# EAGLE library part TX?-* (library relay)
TX Relais NAiS TX-D RELAYS HIGH INSULATION Conforming to the supplementary insulation class of EN Standards (EN41003) Source: http://www.mew-europe.com/.. en_ds_61022_0007.pdf TX-S RELAYS SMALL POLARIZED RELAY WITH HIGH SENSITIVITY 50mW Source: http://www.mew-europe.com/.. en_ds_61022_0022.pdf

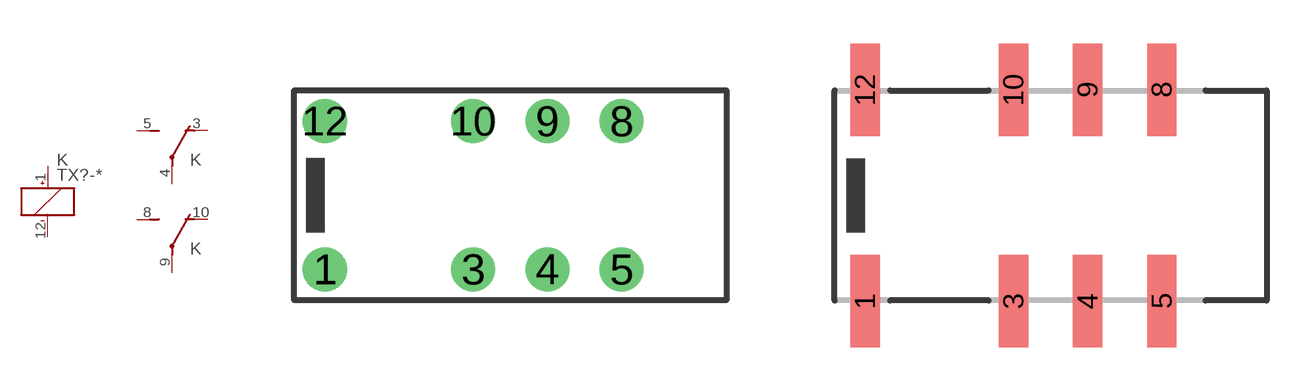
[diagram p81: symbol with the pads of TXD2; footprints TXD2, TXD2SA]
Designator prefix K; gates _=K+- G$1=U G$2=U

## TXD2-1.5V, TXD2-12V, TXD2-24V, TXD2-3V, TXD2-4.5V, TXD2-5V, TXD2-6V, TXD2-9V  [TXD2]
1  _:+  pas
3  G$1:O  pas
4  G$1:P  pas
5  G$1:S  pas
8  G$2:S  pas
9  G$2:P  pas
10  G$2:O  pas
12  _:-  pas

## TXD2SA-1.5V, TXD2SA-12V, TXD2SA-24V, TXD2SA-3V, TXD2SA-4.5V, TXD2SA-5V, TXD2SA-6V, TXD2SA-9V  [TXD2SA]
Pads as for TXD2

## TXD2SL-1.5V, TXD2SL-12V, TXD2SL-24V, TXD2SL-3V, TXD2SL-4.5V, TXD2SL-5V, TXD2SL-6V, TXD2SL-9V  [TXD2SL]
Pads as for TXD2

## TXD2SS-1.5V, TXD2SS-12V, TXD2SS-24V, TXD2SS-3V, TXD2SS-4.5V, TXD2SS-5V, TXD2SS-6V, TXD2SS-9V  [TXD2SS]
Pads as for TXD2

## TXD2-L-1.5V, TXD2-L-12V, TXD2-L-24V, TXD2-L-3V, TXD2-L-4.5V, TXD2-L-5V, TXD2-L-6V, TXD2-L-9V  [TXD2]
1  _:-  pas
3  G$1:O  pas
4  G$1:P  pas
5  G$1:S  pas
8  G$2:S  pas
9  G$2:P  pas
10  G$2:O  pas
12  _:+  pas

## TXD2SA-L-1.5V, TXD2SA-L-12V, TXD2SA-L-24V, TXD2SA-L-3V, TXD2SA-L-4.5V, TXD2SA-L-5V, TXD2SA-L-6V, TXD2SA-L-9V  [TXD2SA]
Pads as for TXD2

## TXD2SL-L-1.5V, TXD2SL-L-12V, TXD2SL-L-24V, TXD2SL-L-3V, TXD2SL-L-4.5V, TXD2SL-L-5V, TXD2SL-L-6V, TXD2SL-L-9V  [TXD2SL]
Pads as for TXD2

## TXD2SS-L-1.5V, TXD2SS-L-12V, TXD2SS-L-24V, TXD2SS-L-3V, TXD2SS-L-4.5V, TXD2SS-L-5V, TXD2SS-L-6V, TXD2SS-L-9V  [TXD2SS]
Pads as for TXD2

## TXD2-2M-1.5V, TXD2-2M-12V, TXD2-2M-24V, TXD2-2M-3V, TXD2-2M-4.5V, TXD2-2M-5V, TXD2-2M-6V, TXD2-2M-9V  [TXD2]
Pads as for TXD2

## TXD2SA-2M-1.5V, TXD2SA-2M-12V, TXD2SA-2M-24V, TXD2SA-2M-3V, TXD2SA-2M-4.5V, TXD2SA-2M-5V, TXD2SA-2M-6V, TXD2SA-2M-9V  [TXD2SA]
Pads as for TXD2

## TXD2SL-2M-1.5V, TXD2SL-2M-12V, TXD2SL-2M-24V, TXD2SL-2M-3V, TXD2SL-2M-4.5V, TXD2SL-2M-5V, TXD2SL-2M-6V, TXD2SL-2M-9V  [TXD2SL]
Pads as for TXD2

## TXD2SS-2M-1.5V, TXD2SS-2M-12V, TXD2SS-2M-24V, TXD2SS-2M-3V, TXD2SS-2M-4.5V, TXD2SS-2M-5V, TXD2SS-2M-6V, TXD2SS-2M-9V  [TXD2SS]
Pads as for TXD2

## TXS2-1.5V, TXS2-12V, TXS2-24V, TXS2-3V, TXS2-4.5V, TXS2-5V, TXS2-6V, TXS2-9V  [TXD2]
Pads as for TXD2

## TXS2-L-1.5V, TXS2-L-12V, TXS2-L-24V, TXS2-L-3V, TXS2-L-4.5V, TXS2-L-5V, TXS2-L-6V, TXS2-L-9V  [TXD2]
Pads as for TXD2

## TXS2SA--1.5V, TXS2SA--12V, TXS2SA--24V, TXS2SA--3V, TXS2SA--4.5V, TXS2SA--5V, TXS2SA--6V, TXS2SA--9V  [TXD2SA]
Pads as for TXD2

## TXS2SL--1.5V, TXS2SL--12V, TXS2SL--24V, TXS2SL--3V, TXS2SL--4.5V, TXS2SL--5V, TXS2SL--6V, TXS2SL--9V  [TXD2SL]
Pads as for TXD2

## TXS2SS--1.5V, TXS2SS--12V, TXS2SS--24V, TXS2SS--3V, TXS2SS--4.5V, TXS2SS--5V, TXS2SS--6V, TXS2SS--9V  [TXD2SS]
Pads as for TXD2

## TXS2SA-L--1.5V, TXS2SA-L--12V, TXS2SA-L--24V, TXS2SA-L--3V, TXS2SA-L--4.5V, TXS2SA-L--5V, TXS2SA-L--6V, TXS2SA-L--9V  [TXD2SA]
Pads as for TXD2

## TXS2SL-L-1.5V, TXS2SL-L-12V, TXS2SL-L-24V, TXS2SL-L-3V, TXS2SL-L-4.5V, TXS2SL-L-5V, TXS2SL-L-6V, TXS2SL-L-9V  [TXD2SL]
Pads as for TXD2

## TXS2SS-L-1.5V, TXS2SS-L-12V, TXS2SS-L-24V, TXS2SS-L-3V, TXS2SS-L-4.5V, TXS2SS-L-5V, TXS2SS-L-6V, TXS2SS-L-9V  [TXD2SS]
Pads as for TXD2

## Footprint TXD2 (pad centres in mm)
HIGH INSULATION RELAYS NAiS Conforming to the supplementary insulation class of EN Standards (EN41003) Source: http://www.mew-europe.com/.. en_ds_61022_0007.pdf
drill 1 round: 1 -6.35,-2.54; 3 -1.27,-2.54; 4 1.27,-2.54; 5 3.81,-2.54; 8 3.81,2.54; 9 1.27,2.54; 10 -1.27,2.54; 12 -6.35,2.54

## Footprint TXD2SA (pad centres in mm)
HIGH INSULATION RELAYS NAiS Conforming to the supplementary insulation class of EN Standards (EN41003) Source: http://www.mew-europe.com/.. en_ds_61022_0007.pdf
smd 1 x 3.16: 1 -6.35,-3.62; 3 -1.27,-3.62; 4 1.27,-3.62; 5 3.81,-3.62; 8 3.81,3.62; 9 1.27,3.62; 10 -1.27,3.62; 12 -6.35,3.62

## Footprint TXD2SL (pad centres in mm)
HIGH INSULATION RELAYS NAiS Conforming to the supplementary insulation class of EN Standards (EN41003) Source: http://www.mew-europe.com/.. en_ds_61022_0007.pdf
smd 1 x 3.16: 1 -6.35,-3.62; 3 -1.27,-3.62; 4 1.27,-3.62; 5 3.81,-3.62; 8 3.81,3.62; 9 1.27,3.62; 10 -1.27,3.62; 12 -6.35,3.62

## Footprint TXD2SS (pad centres in mm)
HIGH INSULATION RELAYS NAiS Conforming to the supplementary insulation class of EN Standards (EN41003) Source: http://www.mew-europe.com/.. en_ds_61022_0007.pdf
smd 1 x 2.16: 1 -6.35,-3.12; 3 -1.27,-3.12; 4 1.27,-3.12; 5 3.81,-3.12; 8 3.81,3.12; 9 1.27,3.12; 10 -1.27,3.12; 12 -6.35,3.12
